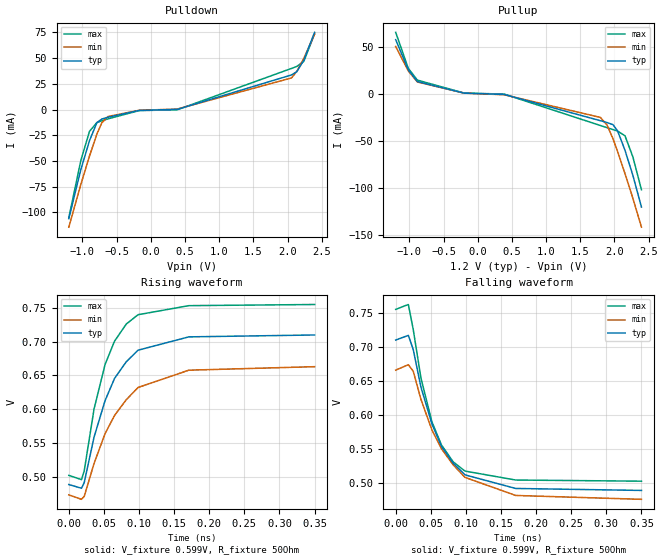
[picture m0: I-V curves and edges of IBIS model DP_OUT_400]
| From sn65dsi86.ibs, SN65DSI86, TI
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|   Model
[Model]   DP_OUT_400
Model_type   Output
Polarity   Non-Inverting
Vmeas = 0.6
Vref = 0.6
Cref = 1pF
Rref = 50
|   typ   min   max
C_comp   0.503pF   0.476pF   0.611pF
[Voltage Range]   1.2   1.14   1.26
[Temperature Range]   27   125   -40
[Pullup Reference]   1.2   1.14   1.26
[Pulldown Reference]   -0   -0   -0
[Power Clamp Reference]   1.2   1.14   1.26
[GND Clamp Reference]   -0   -0   -0
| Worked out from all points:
|   slope of the pulldown table from 0 to 0.18 V, typ, clamps not added: 1.99 kohm
|   slope of the pullup table from 0 to 0.18 V, typ, clamps not added: 1.93 kohm
|   falling waveform, V_fixture 0.599V, R_fixture 50Ohm: 20-80 % time 48.4ps typ, 57.4ps min, 39.2ps max; typ from 0.71 V to 0.488 V
|   rising waveform, V_fixture 0.599V, R_fixture 50Ohm: 20-80 % time 48.3ps typ, 57.2ps min, 39.3ps max; typ from 0.488 V to 0.71 V
[Pulldown]
|   Voltage   I(typ)   I(min)   I(max)
-1.2V     -106mA     -114.3mA   -105.1mA
-1.024V   -58.31mA   -72.74mA   -49.41mA
-897.6mV  -30.2mA    -45.14mA   -21.17mA
-789.6mV  -12.7mA    -23.83mA   -12.58mA
-717.6mV  -9.187mA   -12.86mA   -10.96mA
-624mV    -7.374mA   -6.624mA   -8.926mA
-170.4mV  -758.5uA   -659.2uA   -961.2uA
387.6mV   233.1uA    548.3uA    -152.5uA
2.058V    33.72mA    30.8mA     40.06mA
2.134V    36.79mA    37.04mA    41.92mA
2.238V    47.91mA    49.77mA    46.85mA
2.396V    75.16mA    73.4mA     73.71mA
[Pullup]
|   Voltage   I(typ)   I(min)   I(max)
-1.2V     58.2mA     50.95mA    66.04mA
-1.016V   26.13mA    24.9mA     27.66mA
-883.2mV  13.52mA    13.1mA     15.09mA
-199.2mV  1.217mA    1.207mA    1.308mA
387.6mV   -215.2uA   -540.3uA   177.1uA
1.795V    -28.19mA   -24.71mA   -33.32mA
1.892V    -30.1mA    -32.77mA   -35.61mA
1.979V    -32.43mA   -47.37mA   -37.64mA
2.047V    -39.07mA   -61.13mA   -39.25mA
2.155V    -59.74mA   -84.53mA   -44.28mA
2.27V     -86.35mA   -110.8mA   -66.67mA
2.396V    -120.3mA   -141.7mA   -101.9mA
[Ramp]
R_load = 50
|   typ   min   max
dV/dt_r   0.132786/4.82567e-11   0.113826/5.71754e-11   0.15168/3.92951e-11
dV/dt_f   0.132786/4.84383e-11   0.114069/5.74469e-11   0.15168/3.92059e-11
[Falling Waveform]
V_fixture = 0.599V
V_fixture_min = 0.569V
V_fixture_max = 0.628V
R_fixture = 50Ohm
C_fixture = 0F
|   Time   V(typ)   V(min)   V(max)
0s        709.8mV    665.5mV    754.9mV
18.04ps   716.7mV    673.5mV    762.1mV
25ps      695.8mV    663.9mV    725.2mV
35.98ps   640.4mV    622.4mV    653.8mV
51.67ps   586.2mV    577.3mV    589.2mV
65.16ps   553.3mV    549.9mV    555.5mV
81.91ps   528.5mV    526.1mV    530.5mV
98.67ps   511.4mV    507.7mV    517mV
170.9ps   491.4mV    481.1mV    503.8mV
350ps     488.5mV    475.4mV    502.1mV
[Rising Waveform]
V_fixture = 0.599V
V_fixture_min = 0.569V
V_fixture_max = 0.628V
R_fixture = 50Ohm
C_fixture = 0F
|   Time   V(typ)   V(min)   V(max)
0s        488.5mV    473.2mV    502.1mV
18.04ps   483mV      466.6mV    495.7mV
21.91ps   491.2mV    470.9mV    508.6mV
35.98ps   558.8mV    519.8mV    600.5mV
51.67ps   612.8mV    563.9mV    666.3mV
65.16ps   645.6mV    590.8mV    700.7mV
81.91ps   670.3mV    614.1mV    726.1mV
98.67ps   687.3mV    632.1mV    739.8mV
170.9ps   707mV      657.7mV    753.2mV
350ps     709.8mV    662.9mV    754.9mV
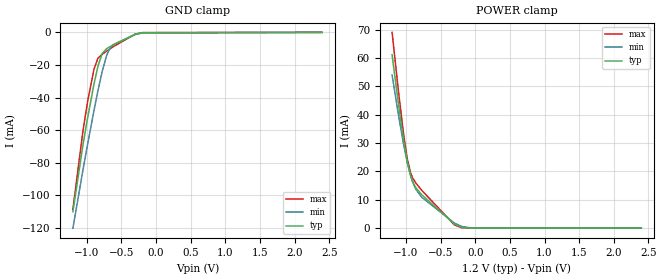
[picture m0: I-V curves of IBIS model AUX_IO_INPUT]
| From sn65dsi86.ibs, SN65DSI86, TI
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|   Model
[Model]   AUX_IO_INPUT
Model_type   Input
Vinl = 0.36
Vinh = 0.84
|   typ   min   max
C_comp   2.622pF   2.343pF   2.762pF
[Voltage Range]   1.2   1.14   1.26
[Temperature Range]   27   125   -40
[Power Clamp Reference]   1.2   1.14   1.26
[GND Clamp Reference]   -0   -0   -0
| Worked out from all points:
|   GND clamp passes 1 mA (typ) near -0.29 V on its own axis
|   POWER clamp passes 1 mA (typ) near -0.27 V on its own axis
[GND Clamp]
|   Voltage   I(typ)   I(min)   I(max)
-1.2V     -110mA     -120.1mA   -108.5mA
-1.056V   -69.26mA   -84.65mA   -60.8mA
-987.6mV  -52.42mA   -68.63mA   -42.37mA
-897.6mV  -32.1mA    -48.34mA   -22.87mA
-840mV    -20.96mA   -36.09mA   -15.92mA
-778.8mV  -13.07mA   -24.23mA   -13.46mA
-714mV    -10.03mA   -14.28mA   -11.55mA
-674.4mV  -8.982mA   -10.41mA   -10.4mA
-616.8mV  -7.594mA   -7.535mA   -8.764mA
-300mV    -1.119mA   -1.286mA   -1.07mA
-195.6mV  -183.6uA   -329.7uA   -163.4uA
2.396V    0A         0A         0A
[POWER Clamp]
|   Voltage   I(typ)   I(min)   I(max)
-1.2V     61.11mA    53.99mA    69.02mA
-1.106V   43.37mA    39.55mA    47.77mA
-1.034V   31.11mA    29.54mA    33.14mA
-980.4mV  23.45mA    23.09mA    24.39mA
-933.6mV  18.55mA    18.56mA    19.53mA
-904.8mV  16.46mA    16.36mA    17.77mA
-858mV    14.26mA    13.74mA    15.93mA
-771.6mV  11.74mA    10.87mA    13.3mA
-300mV    1.431mA    1.775mA    1.129mA
-192mV    271.4uA    557.6uA    128.7uA
-48mV     20.48uA    36.86uA    27.02uA
2.396V    0A         0A         0A
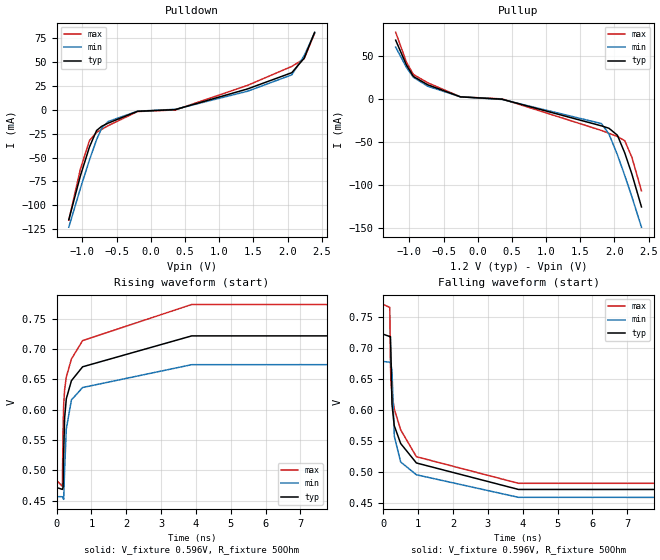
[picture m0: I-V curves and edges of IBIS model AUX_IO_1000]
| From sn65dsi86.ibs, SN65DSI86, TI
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|   Model
[Model]   AUX_IO_1000
Model_type   Output
Polarity   Non-Inverting
Vmeas = 0.6
Vref = 0.6
Cref = 1pF
Rref = 50
|   typ   min   max
C_comp   2.622pF   2.343pF   2.762pF
[Voltage Range]   1.2   1.14   1.26
[Temperature Range]   27   125   -40
[Pullup Reference]   1.2   1.14   1.26
[Pulldown Reference]   -0   -0   -0
[Power Clamp Reference]   1.2   1.14   1.26
[GND Clamp Reference]   -0   -0   -0
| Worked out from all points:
|   slope of the pulldown table from 0 to 0.18 V, typ, clamps not added: 1.88 kohm
|   slope of the pullup table from 0 to 0.18 V, typ, clamps not added: 1.8 kohm
|   falling waveform, V_fixture 0.596V, R_fixture 50Ohm: 20-80 % time 600ps typ, 547ps min, 547ps max; typ from 0.723 V to 0.472 V
|   rising waveform, V_fixture 0.596V, R_fixture 50Ohm: 20-80 % time 576ps typ, 444ps min, 555ps max; typ from 0.472 V to 0.723 V
[Pulldown]
|   Voltage   I(typ)   I(min)   I(max)
-1.2V     -115mA     -122.8mA   -115.5mA
-1.031V   -69.19mA   -82.31mA   -62.15mA
-897.6mV  -38.82mA   -52.39mA   -32.11mA
-793.2mV  -21.57mA   -31.05mA   -23.53mA
-717.6mV  -17.19mA   -19.1mA    -20.39mA
-624mV    -13.91mA   -12.22mA   -16.58mA
-195.6mV  -1.56mA    -1.428mA   -1.821mA
358.8mV   244.1uA    539uA      -125.3uA
1.414V    21.84mA    19.42mA    25.56mA
2.062V    38.84mA    36.58mA    45.41mA
2.242V    53.87mA    56.44mA    53.36mA
2.396V    81.1mA     80.37mA    79.92mA
[Pullup]
|   Voltage   I(typ)   I(min)   I(max)
-1.2V     68.36mA    60.26mA    77.52mA
-1.042V   39.35mA    36.67mA    42.69mA
-940.8mV  26.27mA    25.25mA    28.58mA
-732mV    16.61mA    14.95mA    18.96mA
-253.2mV  2.573mA    2.593mA    2.567mA
355.2mV   -173.8uA   -475.3uA   185.3uA
1.81V     -31.11mA   -28.46mA   -36.45mA
1.921V    -33.95mA   -40.71mA   -39.79mA
2.044V    -42.02mA   -64.75mA   -43.45mA
2.152V    -62.7mA    -88.93mA   -48.45mA
2.256V    -87.14mA   -113.5mA   -67.68mA
2.396V    -125.3mA   -148.8mA   -106.5mA
[Ramp]
R_load = 50
|   typ   min   max
dV/dt_r   0.150591/5.75826e-10   0.133208/4.43544e-10   0.172103/5.54552e-10
dV/dt_f   0.15059/6.00232e-10   0.133211/5.46935e-10   0.172099/5.46784e-10
[Falling Waveform]
V_fixture = 0.596V
V_fixture_min = 0.567V
V_fixture_max = 0.626V
R_fixture = 50Ohm
C_fixture = 0F
|   Time   V(typ)   V(min)   V(max)
0s        722.5mV    678.5mV    770.5mV
183.8ps   718.9mV    677.6mV    765.8mV
202.2ps   718.8mV    676.2mV    675.1mV
214.9ps   695.6mV    675.4mV    648.4mV
245.6ps   609.6mV    663.9mV    626.9mV
312.1ps   575.1mV    558.4mV    602.1mV
495.3ps   546.5mV    516.7mV    568.5mV
946.5ps   515.1mV    496.1mV    525.2mV
3.879ns   472.4mV    459.7mV    482.3mV
200ns     471.6mV    456.5mV    483.6mV
[Rising Waveform]
V_fixture = 0.596V
V_fixture_min = 0.567V
V_fixture_max = 0.626V
R_fixture = 50Ohm
C_fixture = 0F
|   Time   V(typ)   V(min)   V(max)
0s        471.6mV    456.5mV    483.6mV
167.6ps   468.5mV    456.4mV    473.5mV
188.1ps   472.1mV    454mV      568mV
205ps     529.4mV    452.1mV    607.7mV
233ps     586.8mV    501.3mV    633.4mV
280.4ps   618mV      568.1mV    653.9mV
427.5ps   647.9mV    616.1mV    683.7mV
748.4ps   670.8mV    636.6mV    714mV
3.879ns   721.8mV    674.3mV    773.6mV
200ns     722.5mV    678.5mV    770.5mV
